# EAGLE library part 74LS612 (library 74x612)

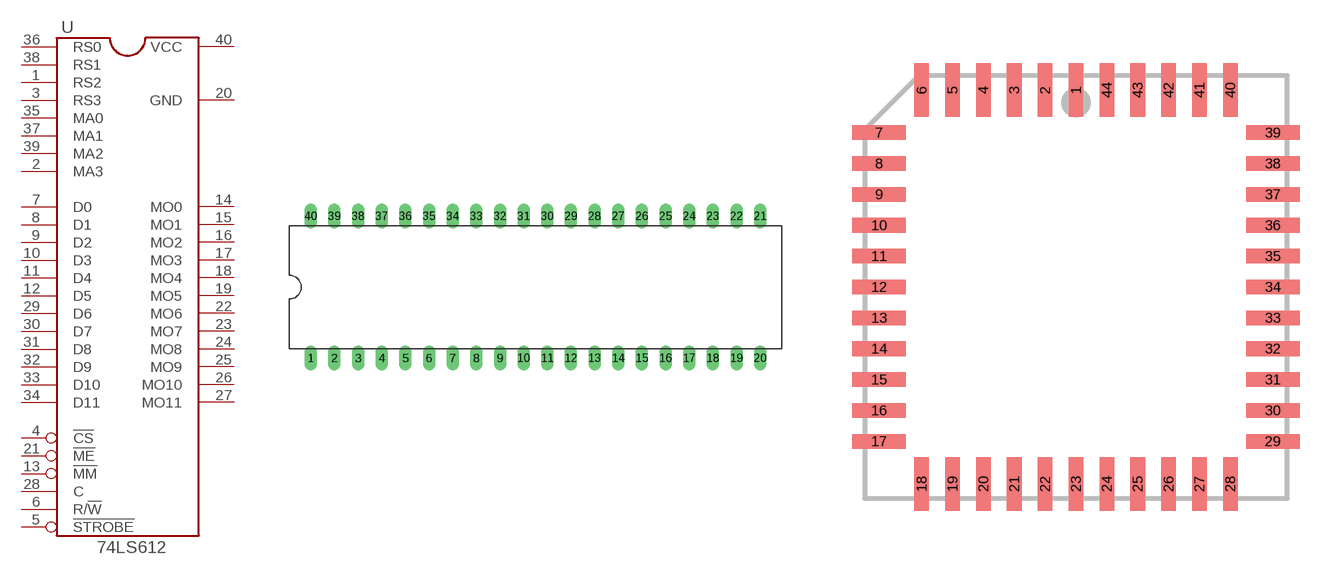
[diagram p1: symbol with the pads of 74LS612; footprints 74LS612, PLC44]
Designator prefix U

## 74LS612LS  [74LS612]
1  RS2  in
2  MA3  in
3  RS3  in
4  !CS  in
5  !STROBE  in
6  R/!W  in
7  D0
8  D1
9  D2
10  D3
11  D4
12  D5
13  !MM  in
14  MO0  out
15  MO1  out
16  MO2  out
17  MO3  out
18  MO4  out
19  MO5  out
20  GND  pwr
21  !ME  in
22  MO6  out
23  MO7  out
24  MO8  out
25  MO9  out
26  MO10  out
27  MO11  out
28  C  in
29  D6
30  D7
31  D8
32  D9
33  D10
34  D11
35  MA0  in
36  RS0  in
37  MA1  in
38  RS1  in
39  MA2  in
40  VCC  pwr

## 74LS612PLCC  [PLC44]
1  RS2  in
2  MA3  in
3  RS3  in
4  !CS  in
5  !STROBE  in
7  R/!W  in
8  D0
9  D1
10  D2
11  D3
12  D4
13  D5
14  !MM  in
15  MO0  out
16  MO1  out
18  MO2  out
19  MO3  out
20  MO4  out
21  MO5  out
22  GND  pwr
23  !ME  in
24  MO6  out
25  MO7  out
26  MO8  out
27  MO9  out
29  MO10  out
30  MO11  out
31  C  in
32  D6
33  D7
34  D8
35  D9
36  D10
37  D11
38  MA0  in
40  RS0  in
41  MA1  in
42  RS1  in
43  MA2  in
44  VCC  pwr

## Footprint 74LS612 (pad centres in mm)
drill 0.813 long: 1 -24.13,-7.62; 2 -21.59,-7.62; 3 -19.05,-7.62; 4 -16.51,-7.62; 5 -13.97,-7.62; 6 -11.43,-7.62; 7 -8.89,-7.62; 8 -6.35,-7.62; 9 -3.81,-7.62; 10 -1.27,-7.62; 11 1.27,-7.62; 12 3.81,-7.62; 13 6.35,-7.62; 14 8.89,-7.62; 15 11.43,-7.62; 16 13.97,-7.62; 17 16.51,-7.62; 18 19.05,-7.62; 19 21.59,-7.62; 20 24.13,-7.62; 21 24.13,7.62; 22 21.59,7.62; 23 19.05,7.62; 24 16.51,7.62; 25 13.97,7.62; 26 11.43,7.62; 27 8.89,7.62; 28 6.35,7.62; 29 3.81,7.62; 30 1.27,7.62; 31 -1.27,7.62; 32 -3.81,7.62; 33 -6.35,7.62; 34 -8.89,7.62; 35 -11.43,7.62; 36 -13.97,7.62; 37 -16.51,7.62; 38 -19.05,7.62; 39 -21.59,7.62; 40 -24.13,7.62

## Footprint PLC44 (pad centres in mm)
smd 0.6 x 2.2: 1 5.08,9.37; 2 3.81,9.37; 3 2.54,9.37; 4 1.27,9.37; 5 0,9.37; 6 -1.27,9.37; 18 -1.27,-6.83; 19 0,-6.83; 20 1.27,-6.83; 21 2.54,-6.83; 22 3.81,-6.83; 23 5.08,-6.83; 24 6.35,-6.83; 25 7.62,-6.83; 26 8.89,-6.83; 27 10.16,-6.83; 28 11.43,-6.83; 40 11.43,9.37; 41 10.16,9.37; 42 8.89,9.37; 43 7.62,9.37; 44 6.35,9.37
smd 2.2 x 0.6: 7 -3.02,7.62; 8 -3.02,6.35; 9 -3.02,5.08; 10 -3.02,3.81; 11 -3.02,2.54; 12 -3.02,1.27; 13 -3.02,0; 14 -3.02,-1.27; 15 -3.02,-2.54; 16 -3.02,-3.81; 17 -3.02,-5.08; 29 13.18,-5.08; 30 13.18,-3.81; 31 13.18,-2.54; 32 13.18,-1.27; 33 13.18,0; 34 13.18,1.27; 35 13.18,2.54; 36 13.18,3.81; 37 13.18,5.08; 38 13.18,6.35; 39 13.18,7.62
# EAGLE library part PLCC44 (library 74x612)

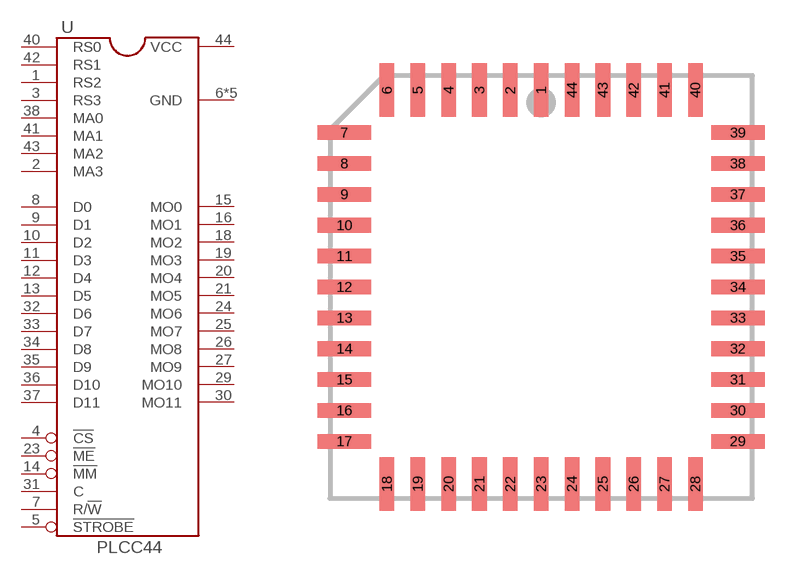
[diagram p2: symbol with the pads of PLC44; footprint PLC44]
Designator prefix -

## PLCC44  [PLC44]
1  RS2  in
2  MA3  in
3  RS3  in
4  !CS  in
5  !STROBE  in
6  GND  pwr
7  R/!W  in
8  D0
9  D1
10  D2
11  D3
12  D4
13  D5
14  !MM  in
15  MO0  out
16  MO1  out
17  GND  pwr
18  MO2  out
19  MO3  out
20  MO4  out
21  MO5  out
22  GND  pwr
23  !ME  in
24  MO6  out
25  MO7  out
26  MO8  out
27  MO9  out
28  GND  pwr
29  MO10  out
30  MO11  out
31  C  in
32  D6
33  D7
34  D8
35  D9
36  D10
37  D11
38  MA0  in
39  GND  pwr
40  RS0  in
41  MA1  in
42  RS1  in
43  MA2  in
44  VCC  pwr

## Footprint PLC44 (pad centres in mm)
smd 0.6 x 2.2: 1 5.08,9.37; 2 3.81,9.37; 3 2.54,9.37; 4 1.27,9.37; 5 0,9.37; 6 -1.27,9.37; 18 -1.27,-6.83; 19 0,-6.83; 20 1.27,-6.83; 21 2.54,-6.83; 22 3.81,-6.83; 23 5.08,-6.83; 24 6.35,-6.83; 25 7.62,-6.83; 26 8.89,-6.83; 27 10.16,-6.83; 28 11.43,-6.83; 40 11.43,9.37; 41 10.16,9.37; 42 8.89,9.37; 43 7.62,9.37; 44 6.35,9.37
smd 2.2 x 0.6: 7 -3.02,7.62; 8 -3.02,6.35; 9 -3.02,5.08; 10 -3.02,3.81; 11 -3.02,2.54; 12 -3.02,1.27; 13 -3.02,0; 14 -3.02,-1.27; 15 -3.02,-2.54; 16 -3.02,-3.81; 17 -3.02,-5.08; 29 13.18,-5.08; 30 13.18,-3.81; 31 13.18,-2.54; 32 13.18,-1.27; 33 13.18,0; 34 13.18,1.27; 35 13.18,2.54; 36 13.18,3.81; 37 13.18,5.08; 38 13.18,6.35; 39 13.18,7.62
